(* Logix 5000 Routine export DNP3Router; software revision 19.01; part 5 of 5 *)

ADD_ON_INSTRUCTION PSDNP3EventG40V02   (* revision 1.0, vendor ProSoft Technology Inc *)
// Processes DNP3 Event and updates corresponding static DNP3 object. (Report by Exception.)
// G40V02 - Analog Output Status - 16bit with Status
VAR_IN_OUT
   EventBuffer : PSDNP3MasterEvent[1]; {required}
END_VAR
VAR_INPUT
   BufferSize : DINT; {required}
   CurrentBufferIndex : DINT; {required}
   Reset : BOOL; {required}
   OutstationNodeAddress : INT; {required}
   OutstationIPAddress0 : INT; {required}
   OutstationIPAddress1 : INT; {required}
   OutstationIPAddress2 : INT; {required}
   OutstationIPAddress3 : INT; {required}
END_VAR
VAR_IN_OUT
   DNP3StaticObject : PSDNP3AnalogOutputStatus16Flag[1]; {required}
END_VAR
VAR_INPUT
   MaxtElementCount : DINT; {required}
END_VAR
VAR_OUTPUT
   EventsProcessed : DINT; {access Read Only, visible}
   LastElementIndex : DINT; {access Read Only, visible}
   LastValue : DINT; {access Read Only, visible}
   LastStatus : SINT; {access Read Only, visible}
   CurrentUnloadIndex : DINT; {access Read Only, visible}
END_VAR
VAR
   UnloadIndex : DINT; {access None}
   EnableInTemp : BOOL; {access None}
   InitialScan : BOOL; {access None}
   EntryValidForProcessing : BOOL; {access None}
   ElementIndex : DINT; {access None}
   NextIndex : DINT; {access None}
   ResetPulse : BOOL; {access None}
   ResetONS : BOOL; {access None}
END_VAR

ROUTINE Logic   (* ladder *)
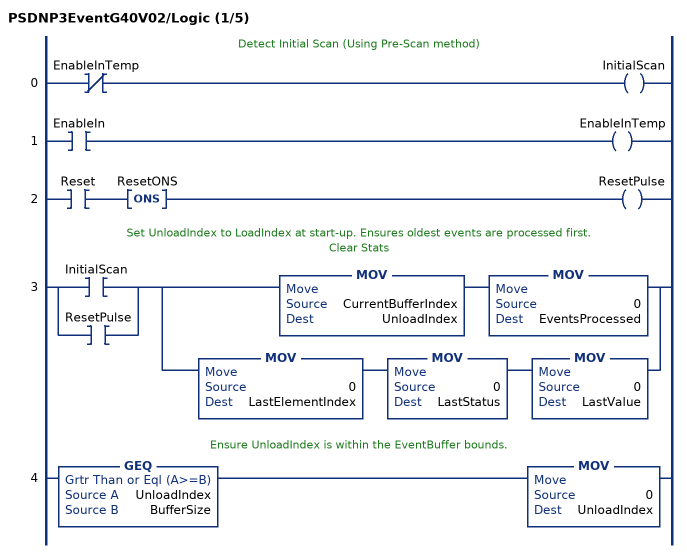
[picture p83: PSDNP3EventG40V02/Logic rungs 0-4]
   // Detect Initial Scan (Using Pre-Scan method)
   0: XIO(EnableInTemp)OTE(InitialScan);
   1: XIC(EnableIn)OTE(EnableInTemp);
   2: XIC(Reset)ONS(ResetONS)OTE(ResetPulse);
   // Set UnloadIndex to LoadIndex at start-up. Ensures oldest events are processed first.
   // Clear Stats
   3: [XIC(InitialScan) ,XIC(ResetPulse) ][MOV(CurrentBufferIndex,UnloadIndex) MOV(0,EventsProcessed) ,MOV(0,LastElementIndex) MOV(0,LastStatus) MOV(0,LastValue) ];
   // Ensure UnloadIndex is within the EventBuffer bounds.
   4: GEQ(UnloadIndex,BufferSize)MOV(0,UnloadIndex);
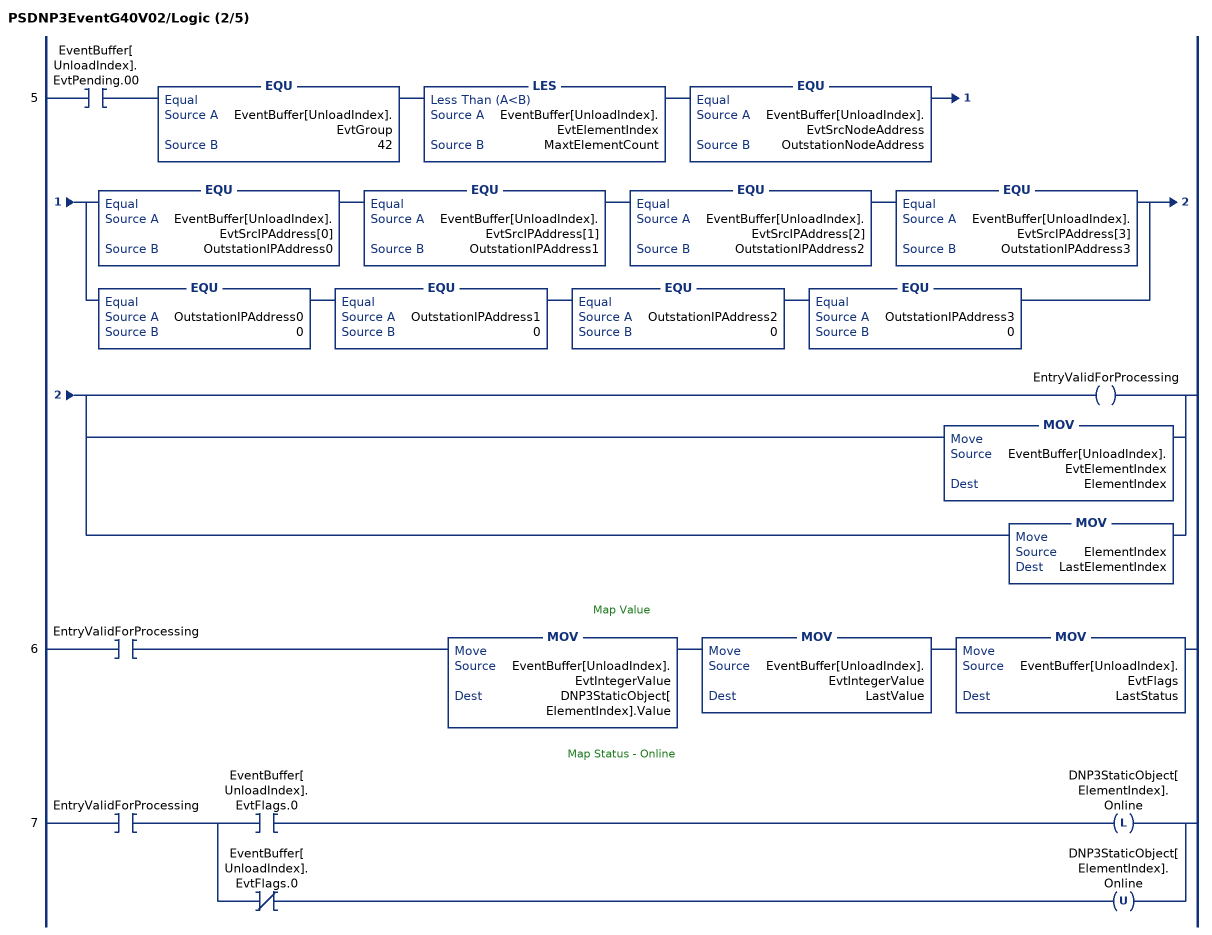
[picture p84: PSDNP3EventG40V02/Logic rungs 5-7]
   5: XIC(EventBuffer[UnloadIndex].EvtPending.00)EQU(EventBuffer[UnloadIndex].EvtGroup,42)LES(EventBuffer[UnloadIndex].EvtElementIndex,MaxtElementCount)EQU(EventBuffer[UnloadIndex].EvtSrcNodeAddress,OutstationNodeAddress)[EQU(EventBuffer[UnloadIndex].EvtSrcIPAddress[0],OutstationIPAddress0) EQU(EventBuffer[UnloadIndex].EvtSrcIPAddress[1],OutstationIPAddress1) EQU(EventBuffer[UnloadIndex].EvtSrcIPAddress[2],OutstationIPAddress2) EQU(EventBuffer[UnloadIndex].EvtSrcIPAddress[3],OutstationIPAddress3) ,EQU(OutstationIPAddress0,0) EQU(OutstationIPAddress1,0) EQU(OutstationIPAddress2,0) EQU(OutstationIPAddress3,0) ][OTE(EntryValidForProcessing) ,MOV(EventBuffer[UnloadIndex].EvtElementIndex,ElementIndex) ,MOV(ElementIndex,LastElementIndex) ];
   // Map Value
   6: XIC(EntryValidForProcessing)MOV(EventBuffer[UnloadIndex].EvtIntegerValue,DNP3StaticObject[ElementIndex].Value)MOV(EventBuffer[UnloadIndex].EvtIntegerValue,LastValue)MOV(EventBuffer[UnloadIndex].EvtFlags,LastStatus);
   // Map Status - Online
   7: XIC(EntryValidForProcessing)[XIC(EventBuffer[UnloadIndex].EvtFlags.0) OTL(DNP3StaticObject[ElementIndex].Online) ,XIO(EventBuffer[UnloadIndex].EvtFlags.0) OTU(DNP3StaticObject[ElementIndex].Online) ];
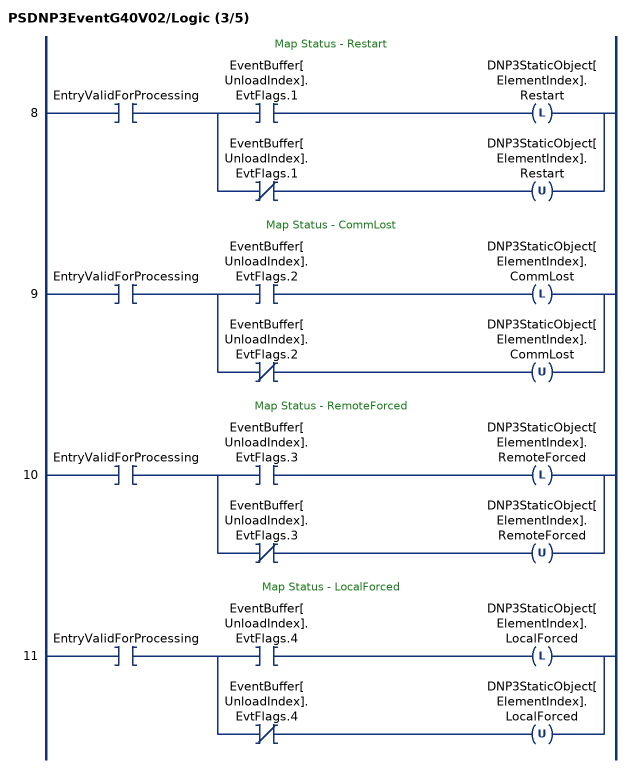
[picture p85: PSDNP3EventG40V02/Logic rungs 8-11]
   // Map Status - Restart
   8: XIC(EntryValidForProcessing)[XIC(EventBuffer[UnloadIndex].EvtFlags.1) OTL(DNP3StaticObject[ElementIndex].Restart) ,XIO(EventBuffer[UnloadIndex].EvtFlags.1) OTU(DNP3StaticObject[ElementIndex].Restart) ];
   // Map Status - CommLost
   9: XIC(EntryValidForProcessing)[XIC(EventBuffer[UnloadIndex].EvtFlags.2) OTL(DNP3StaticObject[ElementIndex].CommLost) ,XIO(EventBuffer[UnloadIndex].EvtFlags.2) OTU(DNP3StaticObject[ElementIndex].CommLost) ];
   // Map Status - RemoteForced
   10: XIC(EntryValidForProcessing)[XIC(EventBuffer[UnloadIndex].EvtFlags.3) OTL(DNP3StaticObject[ElementIndex].RemoteForced) ,XIO(EventBuffer[UnloadIndex].EvtFlags.3) OTU(DNP3StaticObject[ElementIndex].RemoteForced) ];
   // Map Status - LocalForced
   11: XIC(EntryValidForProcessing)[XIC(EventBuffer[UnloadIndex].EvtFlags.4) OTL(DNP3StaticObject[ElementIndex].LocalForced) ,XIO(EventBuffer[UnloadIndex].EvtFlags.4) OTU(DNP3StaticObject[ElementIndex].LocalForced) ];
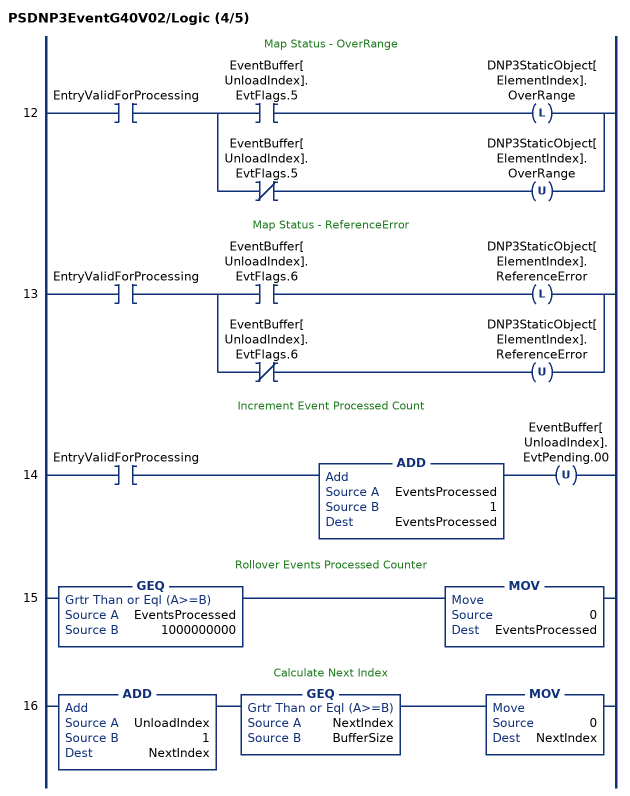
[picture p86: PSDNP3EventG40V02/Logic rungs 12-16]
   // Map Status - OverRange
   12: XIC(EntryValidForProcessing)[XIC(EventBuffer[UnloadIndex].EvtFlags.5) OTL(DNP3StaticObject[ElementIndex].OverRange) ,XIO(EventBuffer[UnloadIndex].EvtFlags.5) OTU(DNP3StaticObject[ElementIndex].OverRange) ];
   // Map Status - ReferenceError
   13: XIC(EntryValidForProcessing)[XIC(EventBuffer[UnloadIndex].EvtFlags.6) OTL(DNP3StaticObject[ElementIndex].ReferenceError) ,XIO(EventBuffer[UnloadIndex].EvtFlags.6) OTU(DNP3StaticObject[ElementIndex].ReferenceError) ];
   // Increment Event Processed Count
   14: XIC(EntryValidForProcessing)ADD(EventsProcessed,1,EventsProcessed)OTU(EventBuffer[UnloadIndex].EvtPending.00);
   // Rollover Events Processed Counter
   15: GEQ(EventsProcessed,1000000000)MOV(0,EventsProcessed);
   // Calculate Next Index
   16: ADD(UnloadIndex,1,NextIndex)GEQ(NextIndex,BufferSize)MOV(0,NextIndex);
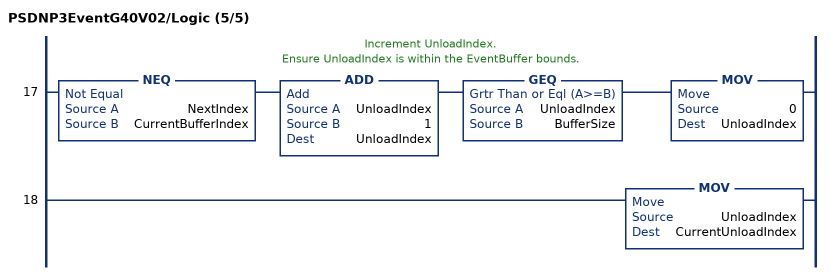
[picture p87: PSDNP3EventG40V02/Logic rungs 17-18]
   // Increment UnloadIndex.
   // Ensure UnloadIndex is within the EventBuffer bounds.
   17: NEQ(NextIndex,CurrentBufferIndex)ADD(UnloadIndex,1,UnloadIndex)GEQ(UnloadIndex,BufferSize)MOV(0,UnloadIndex);
   18: MOV(UnloadIndex,CurrentUnloadIndex);
END_ROUTINE
END_ADD_ON_INSTRUCTION

ADD_ON_INSTRUCTION PSDNP3EventG40V03   (* revision 1.0, vendor ProSoft Technology Inc *)
// Processes DNP3 Event and updates corresponding static DNP3 object. (Report by Exception.)
// G40V03 - Analog Output Status - Real with Status
VAR_IN_OUT
   EventBuffer : PSDNP3MasterEvent[1]; {required}
END_VAR
VAR_INPUT
   BufferSize : DINT; {required}
   CurrentBufferIndex : DINT; {required}
   Reset : BOOL; {required}
   OutstationNodeAddress : INT; {required}
   OutstationIPAddress0 : INT; {required}
   OutstationIPAddress1 : INT; {required}
   OutstationIPAddress2 : INT; {required}
   OutstationIPAddress3 : INT; {required}
END_VAR
VAR_IN_OUT
   DNP3StaticObject : PSDNP3AnalogOutputStatusRealFlag[1]; {required}
END_VAR
VAR_INPUT
   MaxtElementCount : DINT; {required}
END_VAR
VAR_OUTPUT
   EventsProcessed : DINT; {access Read Only, visible}
   LastElementIndex : DINT; {access Read Only, visible}
   LastValue : REAL; {access Read Only, visible}
   LastStatus : SINT; {access Read Only, visible}
   CurrentUnloadIndex : DINT; {access Read Only, visible}
END_VAR
VAR
   UnloadIndex : DINT; {access None}
   EnableInTemp : BOOL; {access None}
   InitialScan : BOOL; {access None}
   EntryValidForProcessing : BOOL; {access None}
   ElementIndex : DINT; {access None}
   NextIndex : DINT; {access None}
   ResetPulse : BOOL; {access None}
   ResetONS : BOOL; {access None}
END_VAR

ROUTINE Logic   (* ladder *)
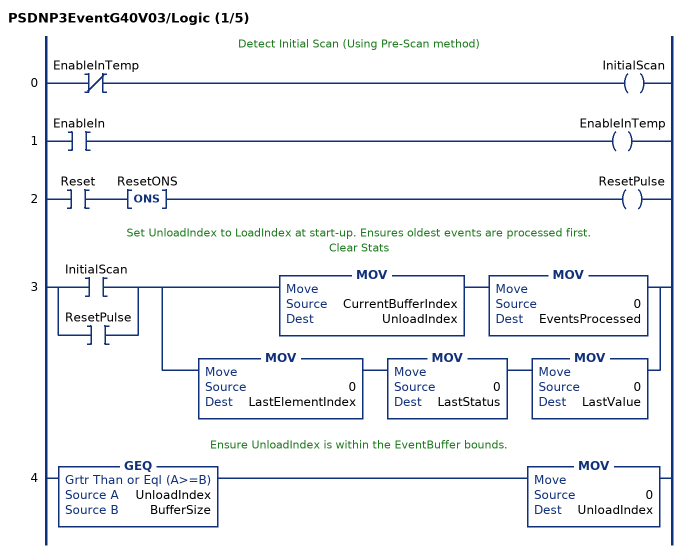
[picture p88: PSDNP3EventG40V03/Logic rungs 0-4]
   // Detect Initial Scan (Using Pre-Scan method)
   0: XIO(EnableInTemp)OTE(InitialScan);
   1: XIC(EnableIn)OTE(EnableInTemp);
   2: XIC(Reset)ONS(ResetONS)OTE(ResetPulse);
   // Set UnloadIndex to LoadIndex at start-up. Ensures oldest events are processed first.
   // Clear Stats
   3: [XIC(InitialScan) ,XIC(ResetPulse) ][MOV(CurrentBufferIndex,UnloadIndex) MOV(0,EventsProcessed) ,MOV(0,LastElementIndex) MOV(0,LastStatus) MOV(0,LastValue) ];
   // Ensure UnloadIndex is within the EventBuffer bounds.
   4: GEQ(UnloadIndex,BufferSize)MOV(0,UnloadIndex);
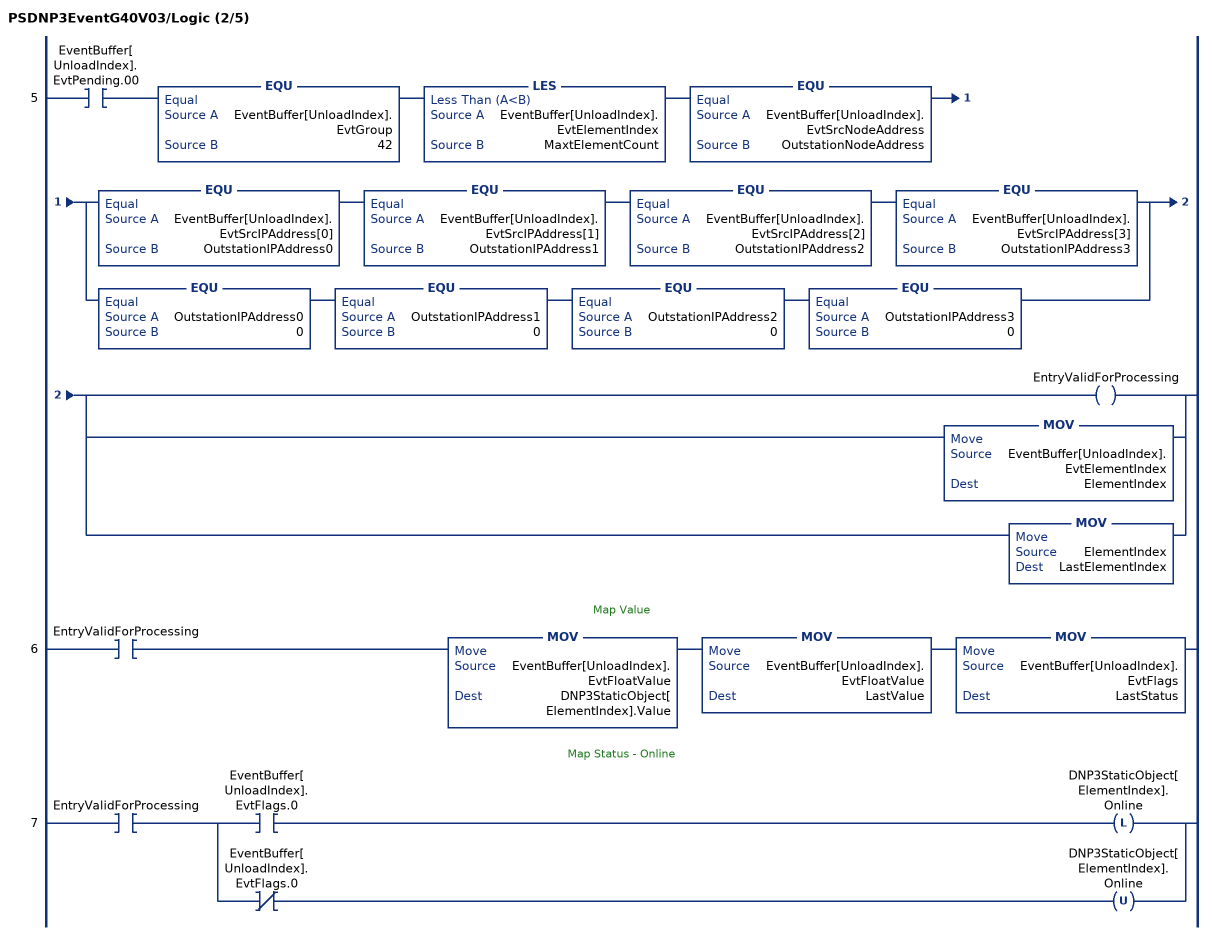
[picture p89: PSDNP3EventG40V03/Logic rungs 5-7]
   5: XIC(EventBuffer[UnloadIndex].EvtPending.00)EQU(EventBuffer[UnloadIndex].EvtGroup,42)LES(EventBuffer[UnloadIndex].EvtElementIndex,MaxtElementCount)EQU(EventBuffer[UnloadIndex].EvtSrcNodeAddress,OutstationNodeAddress)[EQU(EventBuffer[UnloadIndex].EvtSrcIPAddress[0],OutstationIPAddress0) EQU(EventBuffer[UnloadIndex].EvtSrcIPAddress[1],OutstationIPAddress1) EQU(EventBuffer[UnloadIndex].EvtSrcIPAddress[2],OutstationIPAddress2) EQU(EventBuffer[UnloadIndex].EvtSrcIPAddress[3],OutstationIPAddress3) ,EQU(OutstationIPAddress0,0) EQU(OutstationIPAddress1,0) EQU(OutstationIPAddress2,0) EQU(OutstationIPAddress3,0) ][OTE(EntryValidForProcessing) ,MOV(EventBuffer[UnloadIndex].EvtElementIndex,ElementIndex) ,MOV(ElementIndex,LastElementIndex) ];
   // Map Value
   6: XIC(EntryValidForProcessing)MOV(EventBuffer[UnloadIndex].EvtFloatValue,DNP3StaticObject[ElementIndex].Value)MOV(EventBuffer[UnloadIndex].EvtFloatValue,LastValue)MOV(EventBuffer[UnloadIndex].EvtFlags,LastStatus);
   // Map Status - Online
   7: XIC(EntryValidForProcessing)[XIC(EventBuffer[UnloadIndex].EvtFlags.0) OTL(DNP3StaticObject[ElementIndex].Online) ,XIO(EventBuffer[UnloadIndex].EvtFlags.0) OTU(DNP3StaticObject[ElementIndex].Online) ];
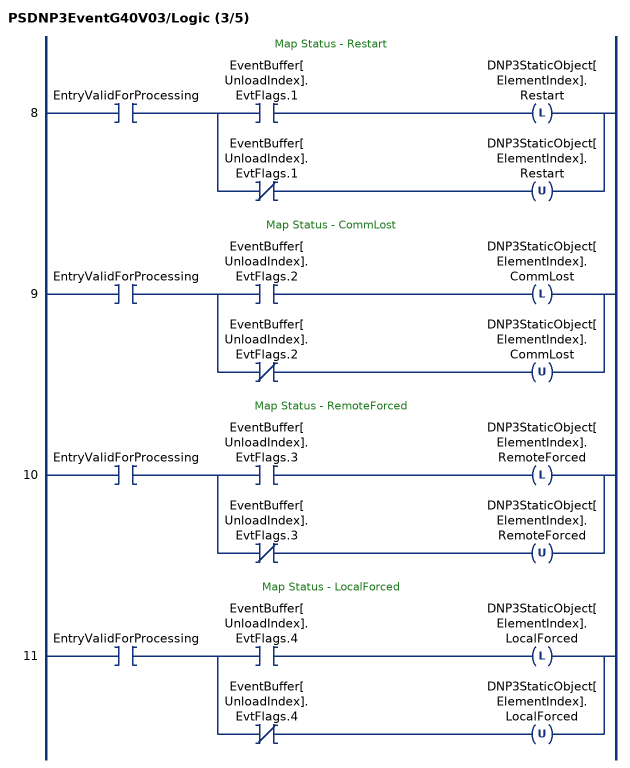
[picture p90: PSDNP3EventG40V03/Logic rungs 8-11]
   // Map Status - Restart
   8: XIC(EntryValidForProcessing)[XIC(EventBuffer[UnloadIndex].EvtFlags.1) OTL(DNP3StaticObject[ElementIndex].Restart) ,XIO(EventBuffer[UnloadIndex].EvtFlags.1) OTU(DNP3StaticObject[ElementIndex].Restart) ];
   // Map Status - CommLost
   9: XIC(EntryValidForProcessing)[XIC(EventBuffer[UnloadIndex].EvtFlags.2) OTL(DNP3StaticObject[ElementIndex].CommLost) ,XIO(EventBuffer[UnloadIndex].EvtFlags.2) OTU(DNP3StaticObject[ElementIndex].CommLost) ];
   // Map Status - RemoteForced
   10: XIC(EntryValidForProcessing)[XIC(EventBuffer[UnloadIndex].EvtFlags.3) OTL(DNP3StaticObject[ElementIndex].RemoteForced) ,XIO(EventBuffer[UnloadIndex].EvtFlags.3) OTU(DNP3StaticObject[ElementIndex].RemoteForced) ];
   // Map Status - LocalForced
   11: XIC(EntryValidForProcessing)[XIC(EventBuffer[UnloadIndex].EvtFlags.4) OTL(DNP3StaticObject[ElementIndex].LocalForced) ,XIO(EventBuffer[UnloadIndex].EvtFlags.4) OTU(DNP3StaticObject[ElementIndex].LocalForced) ];
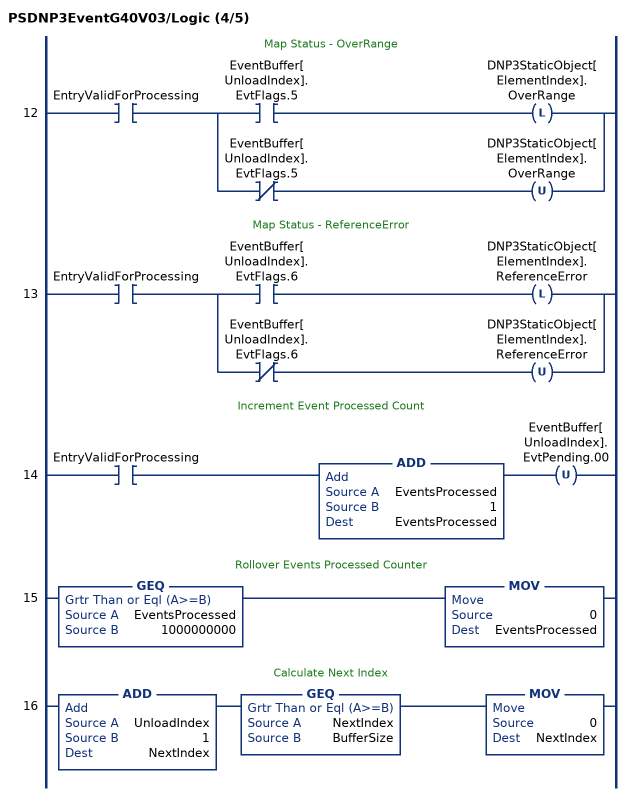
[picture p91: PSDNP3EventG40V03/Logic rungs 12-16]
   // Map Status - OverRange
   12: XIC(EntryValidForProcessing)[XIC(EventBuffer[UnloadIndex].EvtFlags.5) OTL(DNP3StaticObject[ElementIndex].OverRange) ,XIO(EventBuffer[UnloadIndex].EvtFlags.5) OTU(DNP3StaticObject[ElementIndex].OverRange) ];
   // Map Status - ReferenceError
   13: XIC(EntryValidForProcessing)[XIC(EventBuffer[UnloadIndex].EvtFlags.6) OTL(DNP3StaticObject[ElementIndex].ReferenceError) ,XIO(EventBuffer[UnloadIndex].EvtFlags.6) OTU(DNP3StaticObject[ElementIndex].ReferenceError) ];
   // Increment Event Processed Count
   14: XIC(EntryValidForProcessing)ADD(EventsProcessed,1,EventsProcessed)OTU(EventBuffer[UnloadIndex].EvtPending.00);
   // Rollover Events Processed Counter
   15: GEQ(EventsProcessed,1000000000)MOV(0,EventsProcessed);
   // Calculate Next Index
   16: ADD(UnloadIndex,1,NextIndex)GEQ(NextIndex,BufferSize)MOV(0,NextIndex);
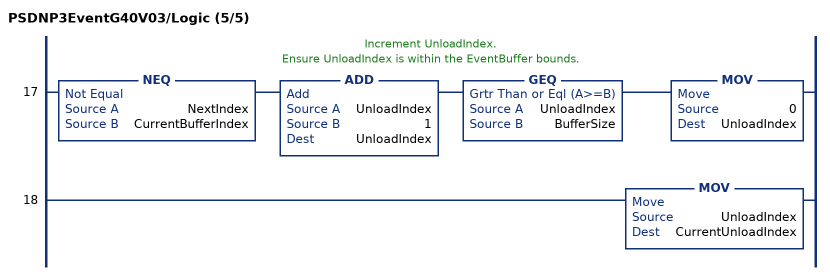
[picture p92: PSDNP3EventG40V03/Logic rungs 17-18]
   // Increment UnloadIndex.
   // Ensure UnloadIndex is within the EventBuffer bounds.
   17: NEQ(NextIndex,CurrentBufferIndex)ADD(UnloadIndex,1,UnloadIndex)GEQ(UnloadIndex,BufferSize)MOV(0,UnloadIndex);
   18: MOV(UnloadIndex,CurrentUnloadIndex);
END_ROUTINE
END_ADD_ON_INSTRUCTION

VAR_GLOBAL   (* controller tags *)
   PLX51DNPMOutput : PLX51DNPOutput;
   PLX51DNPMInput : PLX51DNPInput;
END_VAR

PROGRAM MainProgram

ROUTINE DNP3Router   (* ladder *)
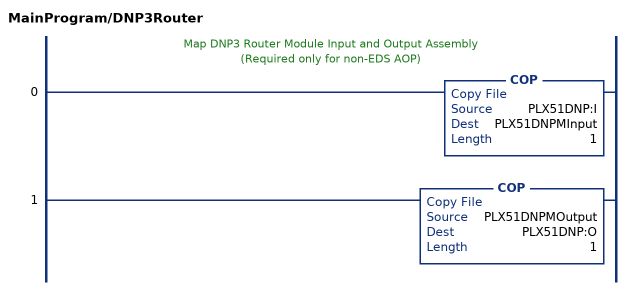
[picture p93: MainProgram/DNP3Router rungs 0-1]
   // Map DNP3 Router Module Input and Output Assembly
   //  (Required only for non-EDS AOP)
   0: COP(PLX51DNP:I,PLX51DNPMInput,1);
   1: COP(PLX51DNPMOutput,PLX51DNP:O,1);
END_ROUTINE
END_PROGRAM
